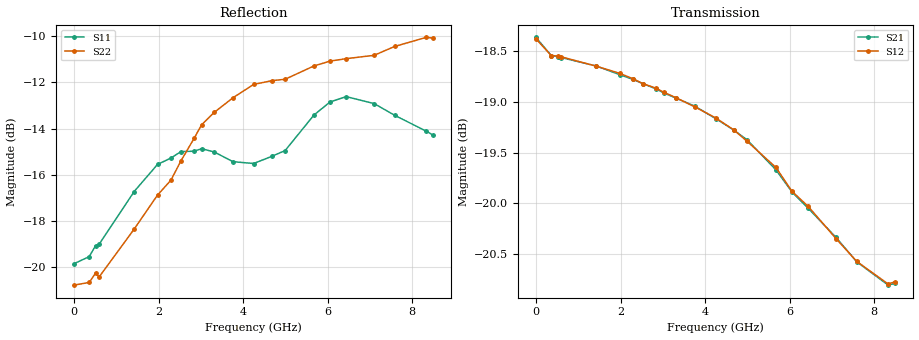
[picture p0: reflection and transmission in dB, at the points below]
! device id: pe43620
! dir: c:\dsa\pe43620\data\pe43620\-40c\3p300v\18p00db
! Serial: 1001
! Insertion: A
! Temp: -40C
! VDD: 3.300V
! Attenuation Step: 18.00dB
! IDD: 7.429295e-03mA
! FILE NAME
! DATE 10-22-2008 14:40:21
! CORRECTED  DATA
#  Hz  S  RI  R  50.00
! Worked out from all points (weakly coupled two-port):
!   401 points, 300 kHz to 8.5 GHz, reference 50 ohm
!   highest |S21| = -18.36 dB at 300 kHz (marker M1); lowest = -20.8 dB at 8.33 GHz (marker M2)
!   lowest |S11| = -19.9 dB at 300 kHz (marker M3), VSWR 1.23, Z = 40.8 + j0.0234 ohm
!   |S11| at or under -10 dB: start of sweep to end of sweep
!   |S22| runs from -20.9 to -10.0 dB; largest |S21 - S12| = 0.00058
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300000  -0.1017 0.000283  0.1207 -0.000263  0.1205 -0.000122  -0.0914 6.27e-05
3.615373e8  -0.1053 0.00347  0.1181 -0.00578  0.1181 -0.00581  -0.0922 -0.00888
5.10282e8  -0.1112 0.0039  0.1178 -0.00808  0.1179 -0.00811  -0.0961 -0.0133
5.95279e8  -0.112 0.00383  0.1176 -0.00942  0.1177 -0.00939  -0.094 -0.015
1.424e9  -0.1451 -0.0143  0.1147 -0.0223  0.1147 -0.0222  -0.1157 -0.035
1.97648e9  -0.1617 -0.0414  0.1116 -0.0306  0.1118 -0.0305  -0.1354 -0.0467
2.295219e9  -0.1634 -0.0547  0.1095 -0.0354  0.1096 -0.0354  -0.1466 -0.0484
2.528961e9  -0.1659 -0.0642  0.1078 -0.0387  0.1078 -0.0387  -0.1624 -0.0496
2.8477e9  -0.1628 -0.0727  0.1054 -0.043  0.1055 -0.043  -0.1831 -0.0527
3.017694e9  -0.1634 -0.0767  0.1039 -0.0453  0.104 -0.0453  -0.1945 -0.0594
3.315183e9  -0.1592 -0.0788  0.1015 -0.0489  0.1016 -0.0488  -0.2055 -0.0675
3.761417e9  -0.1544 -0.0692  0.0977 -0.054  0.0976 -0.054  -0.2224 -0.0688
4.25015e9  -0.1589 -0.0535  0.093 -0.0589  0.0931 -0.0589  -0.2393 -0.068
4.675135e9  -0.1697 -0.0372  0.0889 -0.0625  0.089 -0.0624  -0.2466 -0.0584
4.993874e9  -0.1771 -0.0249  0.0861 -0.0643  0.0858 -0.0644  -0.2522 -0.0395
5.67385e9  -0.2126 -0.019  0.078 -0.0686  0.0782 -0.0688  -0.2727 -0.00378
6.056336e9  -0.2271 -0.0196  0.0732 -0.07  0.0734 -0.0699  -0.2789 0.0181
6.438823e9  -0.2331 -0.0214  0.069 -0.0716  0.0692 -0.0717  -0.2799 0.0409
7.09755e9  -0.2257 -0.0142  0.0611 -0.0743  0.0609 -0.0743  -0.2738 0.0881
7.586282e9  -0.2132 0.00255  0.0557 -0.0752  0.0555 -0.0754  -0.273 0.126
8.330006e9  -0.1927 0.0412  0.0509 -0.0756  0.0508 -0.0758  -0.2694 0.1624
8.5e9  -0.1864 0.0501  0.0502 -0.0763  0.0502 -0.0765  -0.2597 0.1755
